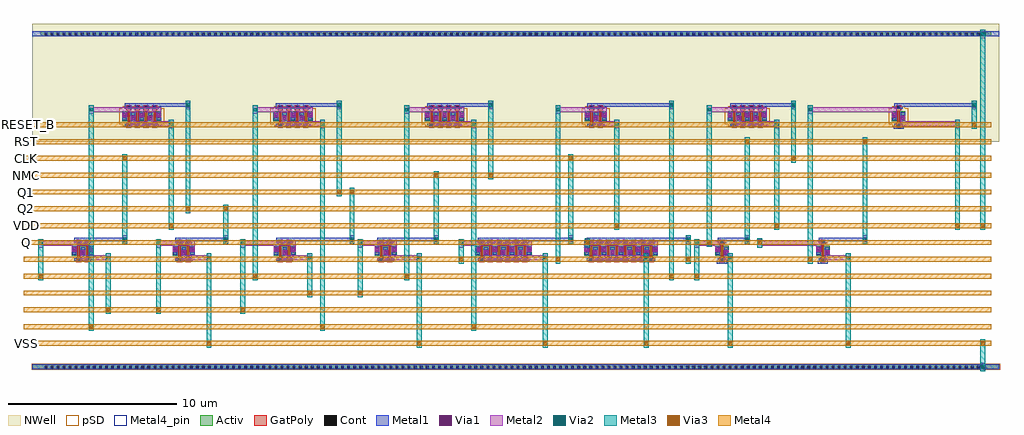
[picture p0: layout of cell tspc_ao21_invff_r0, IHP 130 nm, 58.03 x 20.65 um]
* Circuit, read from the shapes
.subckt tspc_ao21_invff_r0 CLK NMC Q Q1 Q2 RESET_B RST VDD VSS
XM1 dev_n_w0p6_l0p13_ng2_noguard_m1_2/D0 CLK dev_n_w0p6_l0p13_ng1_noguard_m1_10/D VSS sg13_lv_nmos w=0.6u l=0.13u m=2
XM2 VSS Q2 dev_n_w0p6_l0p13_ng2_noguard_m1_2/D0 VSS sg13_lv_nmos w=0.6u l=0.13u m=2
XM3 dev_n_w0p6_l0p13_ng2_noguard_m1_5/D0 Q1 dev_n_w0p6_l0p13_ng2_noguard_m1_2/D0 VSS sg13_lv_nmos w=0.6u l=0.13u m=2
XM4 VSS NMC dev_n_w0p6_l0p13_ng2_noguard_m1_5/D0 VSS sg13_lv_nmos w=0.6u l=0.13u m=2
XM5 VSS CLK dev_p_w0p6_l0p13_ng1_noguard_m1_13/D VSS sg13_lv_nmos w=0.6u l=0.13u m=6
XM6 VSS dev_p_w0p6_l0p13_ng1_noguard_m1_13/D Q VSS sg13_lv_nmos w=0.6u l=0.13u m=8
XM7 VSS RST dev_n_w0p6_l0p13_ng1_noguard_m1_10/D VSS sg13_lv_nmos w=0.6u l=0.13u
XM8 VSS RST Q VSS sg13_lv_nmos w=0.6u l=0.13u
XM9 VDD Q2 dev_p_w0p6_l0p13_ng4_noguard_m1_1/D0 VDD sg13_lv_pmos w=0.6u l=0.13u m=4
XM10 dev_p_w0p6_l0p13_ng4_noguard_m1_1/D0 Q1 dev_n_w0p6_l0p13_ng1_noguard_m1_10/D VDD sg13_lv_pmos w=0.6u l=0.13u m=4
XM11 dev_p_w0p6_l0p13_ng4_noguard_m1_1/D0 NMC dev_n_w0p6_l0p13_ng1_noguard_m1_10/D VDD sg13_lv_pmos w=0.6u l=0.13u m=4
XM12 VDD dev_n_w0p6_l0p13_ng1_noguard_m1_10/D dev_p_w0p6_l0p13_ng1_noguard_m1_13/D VDD sg13_lv_pmos w=0.6u l=0.13u m=2
XM13 VDD CLK Q VDD sg13_lv_pmos w=0.6u l=0.13u m=4
XM14 VDD RESET_B dev_p_w0p6_l0p13_ng1_noguard_m1_13/D VDD sg13_lv_pmos w=0.6u l=0.13u
.ends

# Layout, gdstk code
import gdstk
lib = gdstk.Library(unit=1e-6, precision=1e-09)
def R(c, l, rs):  # rectangles x0, y0, x1, y1
    for r in rs: c.add(gdstk.rectangle(r[:2], r[2:], *l))
def A(c, l, x, y, w, h, nx, ny, dx, dy):  # array of equal rectangles
    R(c, l, [(x+i*dx, y+j*dy, x+i*dx+w, y+j*dy+h) for i in range(nx) for j in range(ny)])
Activ = (1, 0)
GatPoly = (5, 0)
Cont = (6, 0)
Metal1 = (8, 0)
Metal2 = (10, 0)
pSD = (14, 0)
Via1 = (19, 0)
Via2 = (29, 0)
Metal3 = (30, 0)
NWell = (31, 0)
Via3 = (49, 0)
Metal4 = (50, 0)
Metal4_pin = (50, 2)

dev_n_w0p6_l0p13_ng2_nog = lib.new_cell('dev_n_w0p6_l0p13_ng2_noguard_m1')
R(dev_n_w0p6_l0p13_ng2_nog, Activ, [(-0.66,-0.3,0.66,0.3)])
R(dev_n_w0p6_l0p13_ng2_nog, GatPoly, [(-0.405,-0.67,-0.105,-0.37), (0.105,-0.67,0.405,-0.37), (-0.32,-0.37,-0.19,0.37), (0.19,-0.37,0.32,0.37), (-0.405,0.37,-0.105,0.67), (0.105,0.37,0.405,0.67)])
A(dev_n_w0p6_l0p13_ng2_nog, Cont, -0.59, -0.08, 0.16, 0.16, 3, 1, 0.51, 0)
R(dev_n_w0p6_l0p13_ng2_nog, Cont, [(-0.335,-0.6,-0.175,-0.44), (0.175,-0.6,0.335,-0.44), (-0.335,0.44,-0.175,0.6), (0.175,0.44,0.335,0.6)])
A(dev_n_w0p6_l0p13_ng2_nog, Metal1, -0.64, -0.23, 0.26, 0.46, 3, 1, 0.51, 0)
R(dev_n_w0p6_l0p13_ng2_nog, Metal1, [(-0.51,-0.6,0.51,-0.44), (-0.51,0.44,0.51,0.6)])
dev_n_w0p6_l0p13_ng2_nog.add(gdstk.Label('D0', (-0.51,0), layer=8, texttype=25))
dev_n_w0p6_l0p13_ng2_nog.add(gdstk.Label('G', (0.255,0.52), layer=8, texttype=25))
dev_n_w0p6_l0p13_ng2_nog.add(gdstk.Label('G', (-0.255,0.52), layer=8, texttype=25))
dev_n_w0p6_l0p13_ng2_nog.add(gdstk.Label('S1', (0,0), layer=8, texttype=25))

dev_p_w0p6_l0p13_ng4_nog = lib.new_cell('dev_p_w0p6_l0p13_ng4_noguard_m1')
R(dev_p_w0p6_l0p13_ng4_nog, Activ, [(-1.17,-0.3,1.17,0.3)])
A(dev_p_w0p6_l0p13_ng4_nog, GatPoly, -0.915, -0.67, 0.3, 0.3, 4, 2, 0.51, 1.04)
A(dev_p_w0p6_l0p13_ng4_nog, GatPoly, -0.83, -0.37, 0.13, 0.74, 4, 1, 0.51, 0)
A(dev_p_w0p6_l0p13_ng4_nog, Cont, -0.845, -0.6, 0.16, 0.16, 4, 2, 0.51, 1.04)
A(dev_p_w0p6_l0p13_ng4_nog, Cont, -1.1, -0.08, 0.16, 0.16, 5, 1, 0.51, 0)
A(dev_p_w0p6_l0p13_ng4_nog, Metal1, -1.15, -0.23, 0.26, 0.46, 5, 1, 0.51, 0)
R(dev_p_w0p6_l0p13_ng4_nog, Metal1, [(-1.02,-0.6,1.02,-0.44), (-1.02,0.44,1.02,0.6)])
R(dev_p_w0p6_l0p13_ng4_nog, pSD, [(-1.13,-0.6,1.13,-0.48), (-1.35,-0.48,1.35,0.48), (-1.13,0.48,1.13,0.6)])
R(dev_p_w0p6_l0p13_ng4_nog, NWell, [(-1.48,-0.61,1.48,0.61)])
dev_p_w0p6_l0p13_ng4_nog.add(gdstk.Label('D0', (-1.02,0), layer=8, texttype=25))
dev_p_w0p6_l0p13_ng4_nog.add(gdstk.Label('G', (0.765,0.52), layer=8, texttype=25))
dev_p_w0p6_l0p13_ng4_nog.add(gdstk.Label('G', (0.255,0.52), layer=8, texttype=25))
dev_p_w0p6_l0p13_ng4_nog.add(gdstk.Label('G', (-0.255,0.52), layer=8, texttype=25))
dev_p_w0p6_l0p13_ng4_nog.add(gdstk.Label('G', (-0.765,0.52), layer=8, texttype=25))
dev_p_w0p6_l0p13_ng4_nog.add(gdstk.Label('S1', (-0.51,0), layer=8, texttype=25))
dev_p_w0p6_l0p13_ng4_nog.add(gdstk.Label('D2', (0,0), layer=8, texttype=25))
dev_p_w0p6_l0p13_ng4_nog.add(gdstk.Label('S3', (0.51,0), layer=8, texttype=25))

dev_n_w0p6_l0p13_ng6_nog = lib.new_cell('dev_n_w0p6_l0p13_ng6_noguard_m1')
R(dev_n_w0p6_l0p13_ng6_nog, Activ, [(-1.68,-0.3,1.68,0.3)])
A(dev_n_w0p6_l0p13_ng6_nog, GatPoly, -1.425, -0.67, 0.3, 0.3, 6, 2, 0.51, 1.04)
A(dev_n_w0p6_l0p13_ng6_nog, GatPoly, -1.34, -0.37, 0.13, 0.74, 6, 1, 0.51, 0)
A(dev_n_w0p6_l0p13_ng6_nog, Cont, -1.355, -0.6, 0.16, 0.16, 6, 2, 0.51, 1.04)
A(dev_n_w0p6_l0p13_ng6_nog, Cont, -1.61, -0.08, 0.16, 0.16, 7, 1, 0.51, 0)
A(dev_n_w0p6_l0p13_ng6_nog, Metal1, -1.66, -0.23, 0.26, 0.46, 7, 1, 0.51, 0)
R(dev_n_w0p6_l0p13_ng6_nog, Metal1, [(-1.53,-0.6,1.53,-0.44), (-1.53,0.44,1.53,0.6)])
dev_n_w0p6_l0p13_ng6_nog.add(gdstk.Label('D0', (-1.53,0), layer=8, texttype=25))
dev_n_w0p6_l0p13_ng6_nog.add(gdstk.Label('G', (1.275,0.52), layer=8, texttype=25))
dev_n_w0p6_l0p13_ng6_nog.add(gdstk.Label('G', (0.765,0.52), layer=8, texttype=25))
dev_n_w0p6_l0p13_ng6_nog.add(gdstk.Label('G', (0.255,0.52), layer=8, texttype=25))
dev_n_w0p6_l0p13_ng6_nog.add(gdstk.Label('G', (-0.255,0.52), layer=8, texttype=25))
dev_n_w0p6_l0p13_ng6_nog.add(gdstk.Label('G', (-0.765,0.52), layer=8, texttype=25))
dev_n_w0p6_l0p13_ng6_nog.add(gdstk.Label('G', (-1.275,0.52), layer=8, texttype=25))
dev_n_w0p6_l0p13_ng6_nog.add(gdstk.Label('S1', (-1.02,0), layer=8, texttype=25))
dev_n_w0p6_l0p13_ng6_nog.add(gdstk.Label('D2', (-0.51,0), layer=8, texttype=25))
dev_n_w0p6_l0p13_ng6_nog.add(gdstk.Label('S3', (0,0), layer=8, texttype=25))
dev_n_w0p6_l0p13_ng6_nog.add(gdstk.Label('D4', (0.51,0), layer=8, texttype=25))
dev_n_w0p6_l0p13_ng6_nog.add(gdstk.Label('S5', (1.02,0), layer=8, texttype=25))

dev_n_w0p6_l0p13_ng8_nog = lib.new_cell('dev_n_w0p6_l0p13_ng8_noguard_m1')
R(dev_n_w0p6_l0p13_ng8_nog, Activ, [(-2.19,-0.3,2.19,0.3)])
A(dev_n_w0p6_l0p13_ng8_nog, GatPoly, -1.935, -0.67, 0.3, 0.3, 8, 2, 0.51, 1.04)
A(dev_n_w0p6_l0p13_ng8_nog, GatPoly, -1.85, -0.37, 0.13, 0.74, 8, 1, 0.51, 0)
A(dev_n_w0p6_l0p13_ng8_nog, Cont, -1.865, -0.6, 0.16, 0.16, 8, 2, 0.51, 1.04)
A(dev_n_w0p6_l0p13_ng8_nog, Cont, -2.12, -0.08, 0.16, 0.16, 9, 1, 0.51, 0)
A(dev_n_w0p6_l0p13_ng8_nog, Metal1, -2.17, -0.23, 0.26, 0.46, 9, 1, 0.51, 0)
R(dev_n_w0p6_l0p13_ng8_nog, Metal1, [(-2.04,-0.6,2.04,-0.44), (-2.04,0.44,2.04,0.6)])
dev_n_w0p6_l0p13_ng8_nog.add(gdstk.Label('D0', (-2.04,0), layer=8, texttype=25))
dev_n_w0p6_l0p13_ng8_nog.add(gdstk.Label('G', (1.785,0.52), layer=8, texttype=25))
dev_n_w0p6_l0p13_ng8_nog.add(gdstk.Label('G', (1.275,0.52), layer=8, texttype=25))
dev_n_w0p6_l0p13_ng8_nog.add(gdstk.Label('G', (0.765,0.52), layer=8, texttype=25))
dev_n_w0p6_l0p13_ng8_nog.add(gdstk.Label('G', (0.255,0.52), layer=8, texttype=25))
dev_n_w0p6_l0p13_ng8_nog.add(gdstk.Label('G', (-0.255,0.52), layer=8, texttype=25))
dev_n_w0p6_l0p13_ng8_nog.add(gdstk.Label('G', (-0.765,0.52), layer=8, texttype=25))
dev_n_w0p6_l0p13_ng8_nog.add(gdstk.Label('G', (-1.275,0.52), layer=8, texttype=25))
dev_n_w0p6_l0p13_ng8_nog.add(gdstk.Label('G', (-1.785,0.52), layer=8, texttype=25))
dev_n_w0p6_l0p13_ng8_nog.add(gdstk.Label('S1', (-1.53,0), layer=8, texttype=25))
dev_n_w0p6_l0p13_ng8_nog.add(gdstk.Label('D2', (-1.02,0), layer=8, texttype=25))
dev_n_w0p6_l0p13_ng8_nog.add(gdstk.Label('S3', (-0.51,0), layer=8, texttype=25))
dev_n_w0p6_l0p13_ng8_nog.add(gdstk.Label('D4', (0,0), layer=8, texttype=25))
dev_n_w0p6_l0p13_ng8_nog.add(gdstk.Label('S5', (0.51,0), layer=8, texttype=25))
dev_n_w0p6_l0p13_ng8_nog.add(gdstk.Label('D6', (1.02,0), layer=8, texttype=25))
dev_n_w0p6_l0p13_ng8_nog.add(gdstk.Label('S7', (1.53,0), layer=8, texttype=25))

dev_p_w0p6_l0p13_ng2_nog = lib.new_cell('dev_p_w0p6_l0p13_ng2_noguard_m1')
R(dev_p_w0p6_l0p13_ng2_nog, Activ, [(-0.66,-0.3,0.66,0.3)])
R(dev_p_w0p6_l0p13_ng2_nog, GatPoly, [(-0.405,-0.67,-0.105,-0.37), (0.105,-0.67,0.405,-0.37), (-0.32,-0.37,-0.19,0.37), (0.19,-0.37,0.32,0.37), (-0.405,0.37,-0.105,0.67), (0.105,0.37,0.405,0.67)])
A(dev_p_w0p6_l0p13_ng2_nog, Cont, -0.59, -0.08, 0.16, 0.16, 3, 1, 0.51, 0)
R(dev_p_w0p6_l0p13_ng2_nog, Cont, [(-0.335,-0.6,-0.175,-0.44), (0.175,-0.6,0.335,-0.44), (-0.335,0.44,-0.175,0.6), (0.175,0.44,0.335,0.6)])
A(dev_p_w0p6_l0p13_ng2_nog, Metal1, -0.64, -0.23, 0.26, 0.46, 3, 1, 0.51, 0)
R(dev_p_w0p6_l0p13_ng2_nog, Metal1, [(-0.51,-0.6,0.51,-0.44), (-0.51,0.44,0.51,0.6)])
R(dev_p_w0p6_l0p13_ng2_nog, pSD, [(-0.62,-0.6,0.62,-0.48), (-0.84,-0.48,0.84,0.48), (-0.62,0.48,0.62,0.6)])
R(dev_p_w0p6_l0p13_ng2_nog, NWell, [(-0.97,-0.61,0.97,0.61)])
dev_p_w0p6_l0p13_ng2_nog.add(gdstk.Label('D0', (-0.51,0), layer=8, texttype=25))
dev_p_w0p6_l0p13_ng2_nog.add(gdstk.Label('G', (0.255,0.52), layer=8, texttype=25))
dev_p_w0p6_l0p13_ng2_nog.add(gdstk.Label('G', (-0.255,0.52), layer=8, texttype=25))
dev_p_w0p6_l0p13_ng2_nog.add(gdstk.Label('S1', (0,0), layer=8, texttype=25))

dev_n_w0p6_l0p13_ng1_nog = lib.new_cell('dev_n_w0p6_l0p13_ng1_noguard_m1')
R(dev_n_w0p6_l0p13_ng1_nog, Activ, [(-0.405,-0.3,0.405,0.3)])
R(dev_n_w0p6_l0p13_ng1_nog, GatPoly, [(-0.15,-0.67,0.15,-0.37), (-0.065,-0.37,0.065,0.37), (-0.15,0.37,0.15,0.67)])
R(dev_n_w0p6_l0p13_ng1_nog, Cont, [(-0.08,-0.6,0.08,-0.44), (-0.335,-0.08,-0.175,0.08), (0.175,-0.08,0.335,0.08), (-0.08,0.44,0.08,0.6)])
R(dev_n_w0p6_l0p13_ng1_nog, Metal1, [(-0.255,-0.6,0.255,-0.44), (-0.385,-0.23,-0.125,0.23), (0.125,-0.23,0.385,0.23), (-0.255,0.44,0.255,0.6)])
dev_n_w0p6_l0p13_ng1_nog.add(gdstk.Label('D', (-0.255,0), layer=8, texttype=25))
dev_n_w0p6_l0p13_ng1_nog.add(gdstk.Label('S', (0.255,0), layer=8, texttype=25))
dev_n_w0p6_l0p13_ng1_nog.add(gdstk.Label('G', (0,0.52), layer=8, texttype=25))

dev_p_w0p6_l0p13_ng1_nog = lib.new_cell('dev_p_w0p6_l0p13_ng1_noguard_m1')
R(dev_p_w0p6_l0p13_ng1_nog, Activ, [(-0.405,-0.3,0.405,0.3)])
R(dev_p_w0p6_l0p13_ng1_nog, GatPoly, [(-0.15,-0.67,0.15,-0.37), (-0.065,-0.37,0.065,0.37), (-0.15,0.37,0.15,0.67)])
R(dev_p_w0p6_l0p13_ng1_nog, Cont, [(-0.08,-0.6,0.08,-0.44), (-0.335,-0.08,-0.175,0.08), (0.175,-0.08,0.335,0.08), (-0.08,0.44,0.08,0.6)])
R(dev_p_w0p6_l0p13_ng1_nog, Metal1, [(-0.255,-0.6,0.255,-0.44), (-0.385,-0.23,-0.125,0.23), (0.125,-0.23,0.385,0.23), (-0.255,0.44,0.255,0.6)])
R(dev_p_w0p6_l0p13_ng1_nog, pSD, [(-0.365,-0.6,0.365,-0.48), (-0.585,-0.48,0.585,0.48), (-0.365,0.48,0.365,0.6)])
R(dev_p_w0p6_l0p13_ng1_nog, NWell, [(-0.715,-0.61,0.715,0.61)])
dev_p_w0p6_l0p13_ng1_nog.add(gdstk.Label('D', (-0.255,0), layer=8, texttype=25))
dev_p_w0p6_l0p13_ng1_nog.add(gdstk.Label('S', (0.255,0), layer=8, texttype=25))
dev_p_w0p6_l0p13_ng1_nog.add(gdstk.Label('G', (0,0.52), layer=8, texttype=25))

tspc_ao21_invff_r0 = lib.new_cell('tspc_ao21_invff_r0')
R(tspc_ao21_invff_r0, Activ, [(-3,-7.05,54.5,-6.75), (-2.5,12.75,54,13.05)])
A(tspc_ao21_invff_r0, Cont, -2.28, -6.98, 0.16, 0.16, 156, 2, 0.36, 19.8)
A(tspc_ao21_invff_r0, Metal1, -0.145, -0.245, 0.29, 0.29, 4, 1, 6, 0)
A(tspc_ao21_invff_r0, Metal1, 23.835, -0.245, 0.29, 0.29, 3, 1, 1.02, 0)
A(tspc_ao21_invff_r0, Metal1, 30.325, -0.245, 0.29, 0.29, 4, 1, 1.02, 0)
A(tspc_ao21_invff_r0, Metal1, 23.325, -0.045, 0.29, 0.29, 4, 1, 1.02, 0)
A(tspc_ao21_invff_r0, Metal1, 29.815, -0.045, 0.29, 0.29, 5, 1, 1.02, 0)
A(tspc_ao21_invff_r0, Metal1, 21.865, 7.755, 0.29, 0.29, 3, 1, 8.49, 0)
A(tspc_ao21_invff_r0, Metal1, 2.335, 7.955, 0.29, 0.29, 3, 1, 1.02, 0)
A(tspc_ao21_invff_r0, Metal1, 11.335, 7.955, 0.29, 0.29, 3, 1, 1.02, 0)
A(tspc_ao21_invff_r0, Metal1, 20.335, 7.955, 0.29, 0.29, 3, 1, 1.02, 0)
A(tspc_ao21_invff_r0, Metal1, 38.335, 7.955, 0.29, 0.29, 3, 1, 1.02, 0)
A(tspc_ao21_invff_r0, Metal1, 6.105, 8.525, 0.29, 0.045, 3, 1, 9, 0)
A(tspc_ao21_invff_r0, Metal1, 2.48, 8.57, 3.915, 0.21, 3, 1, 9, 0)
A(tspc_ao21_invff_r0, Metal1, 6.105, 8.78, 0.29, 0.035, 3, 1, 9, 0)
R(tspc_ao21_invff_r0, Metal1, [(-3,-7.05,54.5,-6.75), (37.7,-0.75,38.3,-0.59), (43.7,-0.75,44.3,-0.59), (38.11,-0.245,38.4,0.045), (44.11,-0.245,44.4,0.045), (-0.655,-0.045,-0.365,0.245), (0.365,-0.045,0.655,0.245), (5.345,-0.045,5.635,0.245), (6.365,-0.045,6.655,0.245), (11.345,-0.045,11.635,0.245), (12.365,-0.045,12.655,0.245), (17.345,-0.045,17.635,0.245), (18.365,-0.045,18.655,0.245), (37.6,-0.045,37.89,0.245), (43.6,-0.045,43.89,0.245), (2.355,0.525,2.645,0.57), (8.355,0.525,8.645,0.57), (15.855,0.525,16.145,0.57), (20.855,0.525,21.145,0.57), (28.855,0.525,29.145,0.57), (35.855,0.525,36.145,0.57), (39.355,0.525,39.645,0.57), (46.355,0.525,46.645,0.57), (-0.51,0.57,2.645,0.78), (5.49,0.57,8.645,0.78), (11.49,0.57,16.145,0.78), (17.49,0.57,21.145,0.78), (23.47,0.57,29.145,0.78), (29.96,0.57,36.145,0.78), (37.745,0.57,39.645,0.78), (43.745,0.57,46.645,0.78), (2.355,0.78,2.645,0.815), (8.355,0.78,8.645,0.815), (15.855,0.78,16.145,0.815), (20.855,0.78,21.145,0.815), (28.855,0.78,29.145,0.815), (35.855,0.78,36.145,0.815), (39.355,0.78,39.645,0.815), (46.355,0.78,46.645,0.815), (48.2,7.25,48.8,7.41), (2.845,7.755,3.135,8.045), (3.865,7.755,4.155,8.045), (11.845,7.755,12.135,8.045), (12.865,7.755,13.155,8.045), (20.845,7.755,21.135,8.045), (39.865,7.755,40.155,8.045), (48.61,7.755,48.9,8.045), (29.845,7.955,30.135,8.245), (30.865,7.955,31.155,8.245), (48.1,7.955,48.39,8.245), (34.855,8.525,35.145,8.57), (42.105,8.525,42.395,8.57), (52.855,8.525,53.145,8.57), (29.99,8.57,35.145,8.78), (38.48,8.57,42.395,8.78), (48.245,8.57,53.145,8.78), (34.855,8.78,35.145,8.815), (42.105,8.78,42.395,8.815), (52.855,8.78,53.145,8.815), (-3,12.75,54.5,13.05)])
A(tspc_ao21_invff_r0, Metal2, 1.355, -0.65, 0.29, 0.105, 3, 2, 6, 0.395)
A(tspc_ao21_invff_r0, Metal2, -0.145, -0.545, 1.79, 0.29, 3, 1, 6, 0)
A(tspc_ao21_invff_r0, Metal2, -0.145, -0.255, 0.29, 0.3, 4, 1, 6, 0)
A(tspc_ao21_invff_r0, Metal2, 23.835, -0.255, 0.29, 0.3, 3, 1, 1.02, 0)
A(tspc_ao21_invff_r0, Metal2, 30.325, -0.255, 0.29, 0.3, 3, 1, 1.02, 0)
A(tspc_ao21_invff_r0, Metal2, 23.325, -0.045, 0.29, 0.35, 4, 1, 1.02, 0)
A(tspc_ao21_invff_r0, Metal2, 30.835, -0.045, 0.29, 0.35, 4, 1, 1.02, 0)
A(tspc_ao21_invff_r0, Metal2, 5.105, 7.3, 0.29, 0.105, 3, 2, 9, 0.395)
A(tspc_ao21_invff_r0, Metal2, 2.845, 7.405, 2.55, 0.29, 3, 1, 9, 0)
A(tspc_ao21_invff_r0, Metal2, 21.865, 7.695, 0.29, 0.35, 3, 1, 8.49, 0)
A(tspc_ao21_invff_r0, Metal2, 2.335, 7.955, 0.29, 0.3, 3, 1, 1.02, 0)
A(tspc_ao21_invff_r0, Metal2, 11.335, 7.955, 0.29, 0.3, 3, 1, 1.02, 0)
A(tspc_ao21_invff_r0, Metal2, 20.335, 7.955, 0.29, 0.3, 3, 1, 1.02, 0)
A(tspc_ao21_invff_r0, Metal2, 38.335, 7.955, 0.29, 0.3, 3, 1, 1.02, 0)
A(tspc_ao21_invff_r0, Metal2, 10.105, 8.15, 0.29, 0.105, 4, 2, 9, 0.395)
A(tspc_ao21_invff_r0, Metal2, 6.105, 8.42, 0.29, 0.5, 3, 1, 9, 0)
R(tspc_ao21_invff_r0, Metal2, [(53.355,-7.15,53.645,-6.65), (19.855,-0.65,20.145,-0.545), (27.355,-0.65,27.645,-0.545), (33.355,-0.65,33.645,-0.545), (38.355,-0.65,38.645,-0.545), (45.355,-0.65,45.645,-0.545), (17.855,-0.545,20.145,-0.255), (23.835,-0.545,27.645,-0.255), (30.325,-0.545,33.675,-0.255), (38.11,-0.545,38.645,-0.15), (44.11,-0.545,45.645,-0.255), (19.855,-0.255,20.145,-0.15), (27.355,-0.255,27.645,-0.15), (33.355,-0.255,33.675,-0.15), (44.11,-0.255,44.4,0.045), (45.355,-0.255,45.645,-0.15), (33.385,-0.15,33.675,0.045), (38.11,-0.15,38.4,0.045), (-0.655,-0.045,-0.365,0.305), (0.365,-0.045,0.655,0.305), (5.345,-0.045,5.635,0.305), (6.365,-0.045,6.655,0.305), (11.345,-0.045,11.635,0.305), (12.365,-0.045,12.655,0.305), (17.345,-0.045,17.635,0.305), (18.365,-0.045,18.655,0.305), (29.815,-0.045,30.105,0.2), (37.6,-0.045,37.89,0.305), (43.6,-0.045,43.89,0.305), (-2.645,0.2,-2.355,0.305), (4.355,0.2,4.645,0.305), (9.355,0.2,9.645,0.305), (16.355,0.2,16.645,0.305), (22.355,0.2,22.645,0.305), (29.815,0.2,30.145,0.305), (36.355,0.2,36.645,0.305), (40.105,0.2,40.395,0.305), (-2.645,0.305,0.655,0.595), (4.355,0.305,6.655,0.595), (9.355,0.305,12.655,0.595), (16.355,0.305,18.655,0.595), (22.355,0.305,26.675,0.595), (29.815,0.305,34.185,0.595), (36.355,0.305,37.89,0.595), (40.105,0.305,43.89,0.595), (2.355,0.42,2.645,0.92), (8.355,0.42,8.645,0.92), (15.855,0.42,16.145,0.92), (20.855,0.42,21.145,0.92), (28.855,0.42,29.145,0.92), (35.855,0.42,36.145,0.92), (39.355,0.42,39.645,0.92), (46.355,0.42,46.645,0.92), (-2.645,0.595,-2.355,0.7), (4.355,0.595,4.645,0.7), (9.355,0.595,9.645,0.7), (16.355,0.595,16.645,0.7), (22.355,0.595,22.645,0.7), (29.855,0.595,30.145,0.7), (36.355,0.595,36.645,0.7), (40.105,0.595,40.395,0.7), (31.605,7.3,31.895,7.405), (41.105,7.3,41.395,7.405), (51.855,7.3,52.145,7.405), (30.355,7.405,31.895,7.695), (38.845,7.405,41.395,7.695), (48.61,7.405,52.145,7.695), (2.845,7.695,3.135,8.045), (3.865,7.695,4.155,8.045), (11.845,7.695,12.135,8.045), (12.865,7.695,13.155,8.045), (20.845,7.695,21.135,8.045), (31.605,7.695,31.895,7.8), (39.865,7.695,40.155,8.045), (41.105,7.695,41.395,7.8), (48.61,7.695,48.9,8.045), (51.855,7.695,52.145,7.8), (29.845,7.955,30.135,8.255), (30.865,7.955,31.155,8.255), (48.1,7.955,48.39,8.255), (0.355,8.15,0.645,8.255), (43.105,8.15,43.395,8.255), (0.355,8.255,4.665,8.545), (10.105,8.255,13.665,8.545), (19.105,8.255,22.665,8.545), (28.105,8.255,31.155,8.545), (37.105,8.255,40.665,8.545), (43.105,8.255,48.39,8.545), (34.855,8.42,35.145,8.92), (42.105,8.42,42.395,8.92), (52.855,8.42,53.145,8.92), (0.355,8.545,0.645,8.65), (43.105,8.545,43.395,8.65), (53.355,12.65,53.645,13.15)])
R(tspc_ao21_invff_r0, pSD, [(-3.03,-7.08,54.53,-6.72)])
A(tspc_ao21_invff_r0, Via1, -0.095, -0.195, 0.19, 0.19, 4, 1, 6, 0)
A(tspc_ao21_invff_r0, Via1, 23.885, -0.195, 0.19, 0.19, 3, 1, 1.02, 0)
A(tspc_ao21_invff_r0, Via1, 30.375, -0.195, 0.19, 0.19, 4, 1, 1.02, 0)
A(tspc_ao21_invff_r0, Via1, 23.375, 0.005, 0.19, 0.19, 4, 1, 1.02, 0)
A(tspc_ao21_invff_r0, Via1, 29.865, 0.005, 0.19, 0.19, 5, 1, 1.02, 0)
A(tspc_ao21_invff_r0, Via1, 21.915, 7.805, 0.19, 0.19, 3, 1, 8.49, 0)
A(tspc_ao21_invff_r0, Via1, 2.385, 8.005, 0.19, 0.19, 3, 1, 1.02, 0)
A(tspc_ao21_invff_r0, Via1, 11.385, 8.005, 0.19, 0.19, 3, 1, 1.02, 0)
A(tspc_ao21_invff_r0, Via1, 20.385, 8.005, 0.19, 0.19, 3, 1, 1.02, 0)
A(tspc_ao21_invff_r0, Via1, 38.385, 8.005, 0.19, 0.19, 3, 1, 1.02, 0)
A(tspc_ao21_invff_r0, Via1, 6.155, 8.575, 0.19, 0.19, 3, 1, 9, 0)
R(tspc_ao21_invff_r0, Via1, [(53.405,-6.995,53.595,-6.805), (38.16,-0.195,38.35,-0.005), (44.16,-0.195,44.35,-0.005), (-0.605,0.005,-0.415,0.195), (0.415,0.005,0.605,0.195), (5.395,0.005,5.585,0.195), (6.415,0.005,6.605,0.195), (11.395,0.005,11.585,0.195), (12.415,0.005,12.605,0.195), (17.395,0.005,17.585,0.195), (18.415,0.005,18.605,0.195), (37.65,0.005,37.84,0.195), (43.65,0.005,43.84,0.195), (2.405,0.575,2.595,0.765), (8.405,0.575,8.595,0.765), (15.905,0.575,16.095,0.765), (20.905,0.575,21.095,0.765), (28.905,0.575,29.095,0.765), (35.905,0.575,36.095,0.765), (39.405,0.575,39.595,0.765), (46.405,0.575,46.595,0.765), (2.895,7.805,3.085,7.995), (3.915,7.805,4.105,7.995), (11.895,7.805,12.085,7.995), (12.915,7.805,13.105,7.995), (20.895,7.805,21.085,7.995), (39.915,7.805,40.105,7.995), (48.66,7.805,48.85,7.995), (29.895,8.005,30.085,8.195), (30.915,8.005,31.105,8.195), (48.15,8.005,48.34,8.195), (34.905,8.575,35.095,8.765), (42.155,8.575,42.345,8.765), (52.905,8.575,53.095,8.765), (53.405,12.805,53.595,12.995)])
A(tspc_ao21_invff_r0, Via2, 1.405, -0.495, 0.19, 0.19, 3, 1, 6, 0)
A(tspc_ao21_invff_r0, Via2, 5.155, 7.455, 0.19, 0.19, 3, 1, 9, 0)
A(tspc_ao21_invff_r0, Via2, 10.155, 8.305, 0.19, 0.19, 4, 1, 9, 0)
A(tspc_ao21_invff_r0, Via2, 6.155, 8.575, 0.19, 0.19, 3, 1, 9, 0)
R(tspc_ao21_invff_r0, Via2, [(53.405,-6.995,53.595,-6.805), (19.905,-0.495,20.095,-0.305), (27.405,-0.495,27.595,-0.305), (33.405,-0.495,33.595,-0.305), (38.405,-0.495,38.595,-0.305), (45.405,-0.495,45.595,-0.305), (-2.595,0.355,-2.405,0.545), (4.405,0.355,4.595,0.545), (9.405,0.355,9.595,0.545), (16.405,0.355,16.595,0.545), (22.405,0.355,22.595,0.545), (29.905,0.355,30.095,0.545), (36.405,0.355,36.595,0.545), (40.155,0.355,40.345,0.545), (2.405,0.575,2.595,0.765), (8.405,0.575,8.595,0.765), (15.905,0.575,16.095,0.765), (20.905,0.575,21.095,0.765), (28.905,0.575,29.095,0.765), (35.905,0.575,36.095,0.765), (39.405,0.575,39.595,0.765), (46.405,0.575,46.595,0.765), (31.655,7.455,31.845,7.645), (41.155,7.455,41.345,7.645), (51.905,7.455,52.095,7.645), (0.405,8.305,0.595,8.495), (43.155,8.305,43.345,8.495), (34.905,8.575,35.095,8.765), (42.155,8.575,42.345,8.765), (52.905,8.575,53.095,8.765), (53.405,12.805,53.595,12.995)])
R(tspc_ao21_invff_r0, Metal3, [(53.355,-7.15,53.645,-5.25), (7.355,-5.75,7.645,-0.15), (19.855,-5.75,20.145,-0.15), (27.355,-5.75,27.645,-0.15), (33.355,-5.75,33.645,-0.15), (38.355,-5.75,38.645,-0.15), (45.355,-5.75,45.645,-0.15), (0.355,-4.75,0.645,8.65), (14.105,-4.75,14.395,7.8), (23.105,-4.75,23.395,7.8), (1.355,-3.75,1.645,-0.15), (4.355,-3.75,4.645,0.7), (9.355,-3.75,9.645,0.7), (13.355,-2.75,13.645,-0.15), (16.355,-2.75,16.645,0.7), (-2.645,-1.75,-2.355,0.7), (10.105,-1.75,10.395,8.65), (19.105,-1.75,19.395,8.65), (34.855,-1.75,35.145,8.92), (36.355,-1.75,36.645,0.7), (22.355,-0.75,22.645,0.7), (28.105,-0.75,28.395,8.65), (35.855,-0.75,36.145,0.92), (43.105,-0.75,43.395,8.65), (29.855,0.2,30.145,0.75), (40.105,0.2,40.395,0.75), (37.105,0.25,37.395,8.65), (2.355,0.42,2.645,5.75), (8.355,0.42,8.645,2.75), (15.855,0.42,16.145,3.75), (20.855,0.42,21.145,4.75), (28.855,0.42,29.145,5.75), (39.355,0.42,39.645,6.75), (46.355,0.42,46.645,6.75), (5.105,1.25,5.395,7.8), (31.605,1.25,31.895,7.8), (41.105,1.25,41.395,7.8), (51.855,1.25,52.145,7.8), (53.355,1.25,53.645,13.15), (6.105,2.25,6.395,8.92), (15.105,3.25,15.395,8.92), (24.105,4.25,24.395,8.92), (42.105,5.25,42.395,8.92), (52.855,7.25,53.145,8.92)])
R(tspc_ao21_invff_r0, NWell, [(-3,6.5,54.5,13.5)])
R(tspc_ao21_invff_r0, Via3, [(7.405,-5.595,7.595,-5.405), (19.905,-5.595,20.095,-5.405), (27.405,-5.595,27.595,-5.405), (33.405,-5.595,33.595,-5.405), (38.405,-5.595,38.595,-5.405), (45.405,-5.595,45.595,-5.405), (53.405,-5.595,53.595,-5.405), (0.405,-4.595,0.595,-4.405), (14.155,-4.595,14.345,-4.405), (23.155,-4.595,23.345,-4.405), (1.405,-3.595,1.595,-3.405), (4.405,-3.595,4.595,-3.405), (9.405,-3.595,9.595,-3.405), (13.405,-2.595,13.595,-2.405), (16.405,-2.595,16.595,-2.405), (-2.595,-1.595,-2.405,-1.405), (10.155,-1.595,10.345,-1.405), (19.155,-1.595,19.345,-1.405), (34.905,-1.595,35.095,-1.405), (36.405,-1.595,36.595,-1.405), (22.405,-0.595,22.595,-0.405), (28.155,-0.595,28.345,-0.405), (35.905,-0.595,36.095,-0.405), (43.155,-0.595,43.345,-0.405), (29.905,0.405,30.095,0.595), (37.155,0.405,37.345,0.595), (40.155,0.405,40.345,0.595), (5.155,1.405,5.345,1.595), (31.655,1.405,31.845,1.595), (41.155,1.405,41.345,1.595), (51.905,1.405,52.095,1.595), (53.405,1.405,53.595,1.595), (6.155,2.405,6.345,2.595), (8.405,2.405,8.595,2.595), (15.155,3.405,15.345,3.595), (15.905,3.405,16.095,3.595), (20.905,4.405,21.095,4.595), (24.155,4.405,24.345,4.595), (2.405,5.405,2.595,5.595), (28.905,5.405,29.095,5.595), (42.155,5.405,42.345,5.595), (39.405,6.405,39.595,6.595), (46.405,6.405,46.595,6.595), (52.905,7.405,53.095,7.595)])
A(tspc_ao21_invff_r0, Metal4, -3.5, -5.645, 57.5, 0.29, 1, 14, 0, 1)
A(tspc_ao21_invff_r0, Metal4_pin, -3.5, 0.355, 0.3, 0.29, 1, 8, 0, 1)
R(tspc_ao21_invff_r0, Metal4_pin, [(-3.5,-5.645,-3.2,-5.355)])
tspc_ao21_invff_r0.add(gdstk.Reference(dev_n_w0p6_l0p13_ng2_nog, (0,0)))
tspc_ao21_invff_r0.add(gdstk.Reference(dev_p_w0p6_l0p13_ng4_nog, (3.5,8)))
tspc_ao21_invff_r0.add(gdstk.Reference(dev_n_w0p6_l0p13_ng2_nog, (6,0)))
tspc_ao21_invff_r0.add(gdstk.Reference(dev_n_w0p6_l0p13_ng2_nog, (12,0)))
tspc_ao21_invff_r0.add(gdstk.Reference(dev_p_w0p6_l0p13_ng4_nog, (12.5,8)))
tspc_ao21_invff_r0.add(gdstk.Reference(dev_n_w0p6_l0p13_ng2_nog, (18,0)))
tspc_ao21_invff_r0.add(gdstk.Reference(dev_p_w0p6_l0p13_ng4_nog, (21.5,8)))
tspc_ao21_invff_r0.add(gdstk.Reference(dev_n_w0p6_l0p13_ng6_nog, (25,0)))
tspc_ao21_invff_r0.add(gdstk.Reference(dev_n_w0p6_l0p13_ng8_nog, (32,0)))
tspc_ao21_invff_r0.add(gdstk.Reference(dev_p_w0p6_l0p13_ng2_nog, (30.5,8)))
tspc_ao21_invff_r0.add(gdstk.Reference(dev_n_w0p6_l0p13_ng1_nog, (38,0)))
tspc_ao21_invff_r0.add(gdstk.Reference(dev_p_w0p6_l0p13_ng4_nog, (39.5,8)))
tspc_ao21_invff_r0.add(gdstk.Reference(dev_n_w0p6_l0p13_ng1_nog, (44,0)))
tspc_ao21_invff_r0.add(gdstk.Reference(dev_p_w0p6_l0p13_ng1_nog, (48.5,8)))
tspc_ao21_invff_r0.add(gdstk.Label('Q2', (-3.35,2.5), layer=50, texttype=25))
tspc_ao21_invff_r0.add(gdstk.Label('Q1', (-3.35,3.5), layer=50, texttype=25))
tspc_ao21_invff_r0.add(gdstk.Label('NMC', (-3.35,4.5), layer=50, texttype=25))
tspc_ao21_invff_r0.add(gdstk.Label('CLK', (-3.35,5.5), layer=50, texttype=25))
tspc_ao21_invff_r0.add(gdstk.Label('Q', (-3.35,0.5), layer=50, texttype=25))
tspc_ao21_invff_r0.add(gdstk.Label('RST', (-3.35,6.5), layer=50, texttype=25))
tspc_ao21_invff_r0.add(gdstk.Label('RESET_B', (-3.35,7.5), layer=50, texttype=25))
tspc_ao21_invff_r0.add(gdstk.Label('VDD', (-3.35,1.5), layer=50, texttype=25))
tspc_ao21_invff_r0.add(gdstk.Label('VSS', (-3.35,-5.5), layer=50, texttype=25))

lib.write_gds('tspc_ao21_invff_r0.gds')
